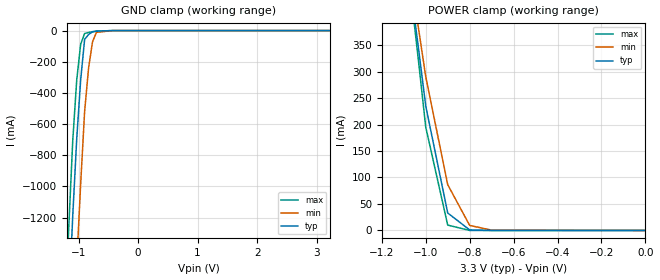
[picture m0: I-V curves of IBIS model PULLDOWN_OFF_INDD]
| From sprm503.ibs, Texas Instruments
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|   Model Cell PULLDOWN_OFF_INDD
[Model]   PULLDOWN_OFF_INDD
Model_type   Input
Polarity   Non-Inverting
Vinl =  0.8
Vinh =  2
C_comp   0.8695239p   0.8584917p   0.8767336p
[Model Spec]
Vinl   0.8   0.8   0.8
Vinh   2   2   2
[Temperature Range]   25   125   -40
[Voltage Range]   3.3   3.14   3.47
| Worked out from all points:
|   GND clamp passes 1 mA (typ) near -0.58 V on its own axis
|   POWER clamp passes 1 mA (typ) near -0.80 V on its own axis
[POWER_clamp]
|   voltage   I(typ)   I(min)   I(max)
-3.3V     9.572A     8.115A     10.87A
-1.067V   452.1mA    472.8mA    444.6mA
-1.033V   343.5mA    381.5mA    319.8mA
-1V       234.9mA    290.2mA    195mA
-900mV    33.01mA    86.46mA    10.14mA
-800mV    1.012mA    9.543mA    89.45uA
-700mV    23.28uA    605.6uA    712.3nA
-11.55fV  368.6pA    11.76nA    170.4pA
[GND_clamp]
|   voltage   I(typ)   I(min)   I(max)
-3.3V     -22.43A    -23.21A    -22A
-1.233V   -2.35A     -3.221A    -1.845A
-1.167V   -1.763A    -2.627A    -1.266A
-1.1V     -1.191A    -2.042A    -709.3mA
-1.033V   -696.7mA   -1.495A    -318mA
-966.7mV  -318.5mA   -986.5mA   -87.81mA
-900mV    -56.17mA   -518.4mA   -18.7mA
-833.3mV  -25.14mA   -240.3mA   -12.29mA
-766.7mV  -7.667mA   -71.25mA   -7.131mA
-700mV    -3.749mA   -11.22mA   -3.214mA
-433.3mV  -54.32uA   -212.5uA   -16.61uA
3.233V    348.5pA    12.42nA    146.2pA
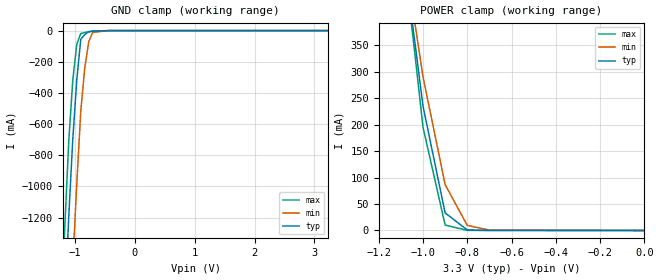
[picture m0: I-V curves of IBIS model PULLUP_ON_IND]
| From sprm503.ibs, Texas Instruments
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|   Model Cell PULLUP_ON_IND
[Model]   PULLUP_ON_IND
Model_type   Input
Polarity   Non-Inverting
Vinl =  0.8
Vinh =  2
C_comp   0.8695239p   0.8584917p   0.8767336p
[Model Spec]
Vinl   0.8   0.8   0.8
Vinh   2   2   2
[Temperature Range]   25   125   -40
[Voltage Range]   3.3   3.14   3.47
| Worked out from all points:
|   GND clamp passes 1 mA (typ) near -0.58 V on its own axis
|   POWER clamp passes 1 mA (typ) near -0.79 V on its own axis
[POWER_clamp]
|   voltage   I(typ)   I(min)   I(max)
-3.3V     9.572A     8.116A     10.87A
-1.067V   452.2mA    472.9mA    444.7mA
-1.033V   343.6mA    381.6mA    319.9mA
-1V       234.9mA    290.3mA    195.1mA
-900mV    33.09mA    86.55mA    10.25mA
-800mV    1.079mA    9.609mA    183.8uA
-700mV    81.06uA    649.2uA    81.95uA
-11.55fV  364pA      11.75nA    165.7pA
[GND_clamp]
|   voltage   I(typ)   I(min)   I(max)
-3.3V     -22.43A    -23.21A    -22A
-1.233V   -2.35A     -3.221A    -1.845A
-1.167V   -1.763A    -2.627A    -1.266A
-1.1V     -1.191A    -2.042A    -709.3mA
-1.033V   -696.7mA   -1.495A    -318mA
-966.7mV  -318.5mA   -986.5mA   -87.89mA
-900mV    -56.21mA   -518.4mA   -18.84mA
-833.3mV  -25.22mA   -240.3mA   -12.44mA
-766.7mV  -7.763mA   -71.27mA   -7.278mA
-700mV    -3.851mA   -11.26mA   -3.361mA
-433.3mV  -158uA     -278.1uA   -165.3uA
3.233V    -4.892uA   4.762uA    -23.3uA
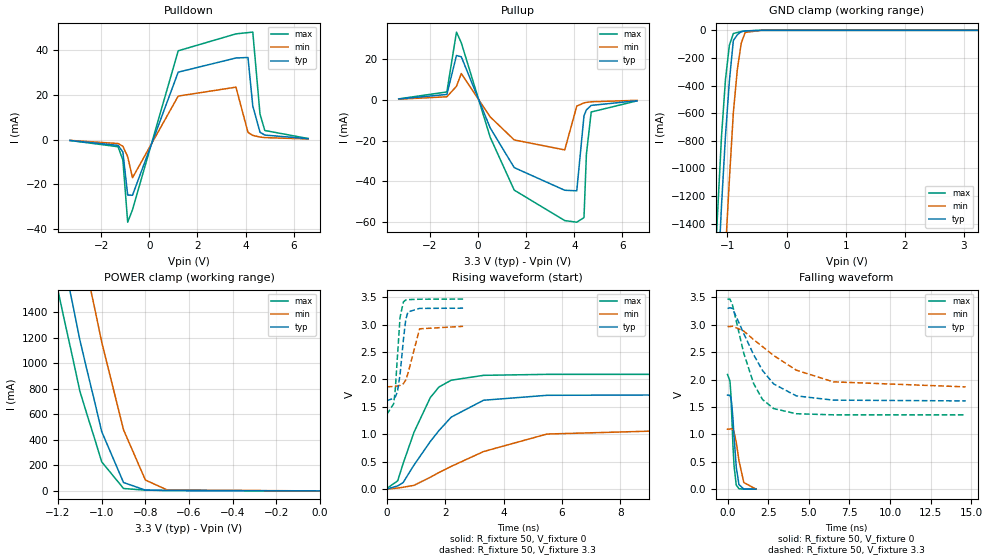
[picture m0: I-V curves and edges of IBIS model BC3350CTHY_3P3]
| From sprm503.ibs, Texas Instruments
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|   Model Cell BC3350CTHY_3P3
|BC3350CTHY_3P3
[Model]   BC3350CTHY_3P3
Model_type   I/O
Polarity   Non-Inverting
Enable   Active-Low
Vinl =  0.8V
Vinh =  2V
Cref =  15.0000pF
Rref =  100.0000M
Vref =  0V
Vmeas =  1.65
C_comp   0.8695239p   0.8584917p   0.8767304p
[Model Spec]
Vinl   0.8V   0.8V   0.8V
Vinh   2V   2V   2V
[Temperature Range]   25   125   -40
[Voltage Range]   3.3   2.97   3.465
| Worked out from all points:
|   slope of the pulldown table from 0 to 0.495 V, typ, clamps not added: 30.2 ohm
|   slope of the pullup table from 0 to 0.495 V, typ, clamps not added: 36.2 ohm
|   GND clamp passes 1 mA (typ) near -0.57 V on its own axis
|   POWER clamp passes 1 mA (typ) near -0.52 V on its own axis
|   rising waveform, R_fixture 50, V_fixture 0: 20-80 % time 1.52ns typ, 2.8ns min, 964ps max; typ from 0.001 V to 1.72 V
|   rising waveform, R_fixture 50, V_fixture 3.3: 20-80 % time 193ps typ, 277ps min, 154ps max; typ from 1.61 V to 3.3 V
|   falling waveform, R_fixture 50, V_fixture 0: 20-80 % time 242ps typ, 371ps min, 190ps max; typ from 1.72 V to 0.002 V
|   falling waveform, R_fixture 50, V_fixture 3.3: 20-80 % time 1.92ns typ, 3.36ns min, 1.32ns max; typ from 3.3 V to 1.61 V
[POWER_clamp]
|   voltage   I(typ)   I(min)   I(max)
-3.3V     22.37A     23.12A     21.96A
-1.2V     2.026A     2.853A     1.569A
-1.167V   1.745A     2.562A     1.307A
-1.133V   1.464A     2.272A     1.044A
-1.1V     1.183A     1.981A     781.8mA
-1.067V   943.8mA    1.709A     597.2mA
-1.033V   704.5mA    1.438A     412.6mA
-1V       465.3mA    1.167A     227.9mA
-900mV    65.74mA    478.8mA    18.97mA
-800mV    6.466mA    85.39mA    6.091mA
-700mV    3.149mA    7.546mA    3.832mA
0V        276.4pA    13.39nA    14.63pA
[Pulldown]
|   voltage   I(typ)   I(min)   I(max)
-3.3V     -379.4uA   -330.9uA   -386.9uA
-1.3V     -2.568mA   -1.749mA   -3.18mA
-1.1V     -5.533mA   -2.961mA   -9.161mA
-900mV    -24.8mA    -7.62mA    -36.98mA
-700mV    -24.92mA   -17.08mA   -31.4mA
1.2V      30.22mA    19.51mA    39.79mA
3.6V      36.57mA    23.5mA     47.37mA
4.1V      36.79mA    3.23mA     47.94mA
4.3V      15.06mA    1.903mA    48.17mA
4.6V      3.307mA    1.155mA    11.41mA
4.8V      2.043mA    911.3uA    4.087mA
6.6V      436uA      308.8uA    502.3uA
[Pullup]
|   voltage   I(typ)   I(min)   I(max)
-3.3V     352.6uA    257.6uA    391.7uA
-1.3V     2.559mA    1.411mA    3.79mA
-900mV    21.62mA    6.557mA    33.08mA
-700mV    21.01mA    12.8mA     27.85mA
500mV     -13.79mA   -8.403mA   -18.35mA
1.5V      -33.25mA   -19.7mA    -44.26mA
3.6V      -44.33mA   -24.58mA   -59.17mA
4.1V      -44.61mA   -3.141mA   -59.96mA
4.4V      -7.896mA   -1.57mA    -57.69mA
4.5V      -4.997mA   -1.34mA    -26.74mA
4.7V      -2.803mA   -1.033mA   -6.023mA
6.6V      -515.4uA   -319.6uA   -597.7uA
[GND_clamp]
|   voltage   I(typ)   I(min)   I(max)
-3.3V     -22.52A    -23.33A    -22.07A
-1.233V   -2.436A    -3.336A    -1.911A
-1.167V   -1.845A    -2.739A    -1.328A
-1.1V     -1.269A    -2.151A    -766.5mA
-1.033V   -763.8mA   -1.597A    -354.9mA
-966.7mV  -365.3mA   -1.079A    -107.1mA
-900mV    -73.52mA   -596.8mA   -23.28mA
-833.3mV  -32.6mA    -287.4mA   -15.31mA
-766.7mV  -9.652mA   -93.47mA   -8.887mA
-700mV    -4.682mA   -15.11mA   -4.019mA
-433.3mV  -68.38uA   -267.7uA   -20.98uA
3.233V    -607.5pA   11.45uA    -20pA
[Ramp]
| variable   typ   min   max
dV/dt_f   1.022976/1.927517n   0.6709498/3.398073n   1.276353/1.319437n
dV/dt_r   1.031671/1.520254n   0.6578422/2.813193n   1.25571/0.9666258n
R_load = 50
[Rising Waveform]
R_fixture = 50
V_fixture = 0
V_fixture_min = 0
V_fixture_max = 0
|   time   V(typ)   V(min)   V(max)
0s        1.187mV    -365.6uV   12.72mV
372ps     59.43mV    20.3mV     151.3mV
558ps     119.7mV    34.65mV    465.9mV
933ps     440.9mV    69.38mV    1.039V
1.491ns   869.1mV    217.2mV    1.67V
1.785ns   1.067V     302.6mV    1.861V
2.205ns   1.312V     414.5mV    1.985V
3.312ns   1.62V      684.7mV    2.074V
5.484ns   1.71V      1.004V     2.092V
11.43ns   1.719V     1.093V     2.092V
[Rising Waveform]
R_fixture = 50
V_fixture = 3.3
V_fixture_min = 2.97
V_fixture_max = 3.465
|   time   V(typ)   V(min)   V(max)
0s        1.612V     1.865V     1.362V
237ps     1.657V     1.87V      1.558V
291ps     1.681V     1.875V     1.821V
363ps     1.772V     1.882V     2.412V
453ps     2.084V     1.891V     3.13V
567ps     2.717V     1.922V     3.412V
648ps     3.088V     1.99V      3.446V
723ps     3.229V     2.105V     3.454V
1.122ns   3.294V     2.922V     3.461V
2.613ns   3.298V     2.967V     3.464V
[Falling Waveform]
R_fixture = 50
V_fixture = 0
V_fixture_min = 0
V_fixture_max = 0
|   time   V(typ)   V(min)   V(max)
0s        1.719V     1.096V     2.094V
150ps     1.713V     1.097V     1.975V
201ps     1.672V     1.101V     1.758V
252ps     1.584V     1.104V     1.406V
336ps     1.281V     1.086V     788.4mV
402ps     958.1mV    1.044V     428.2mV
537ps     402.8mV    856.9mV    77.62mV
705ps     83.71mV    520.9mV    7.935mV
1.002ns   4.674mV    122.6mV    2.2mV
1.749ns   1.531mV    2.984mV    1.095mV
[Falling Waveform]
R_fixture = 50
V_fixture = 3.3
V_fixture_min = 2.97
V_fixture_max = 3.465
|   time   V(typ)   V(min)   V(max)
0s        3.299V     2.97V      3.471V
153ps     3.313V     2.969V     3.469V
306ps     3.299V     2.976V     3.363V
996ps     2.844V     2.888V     2.487V
1.608ns   2.455V     2.73V      1.928V
2.151ns   2.169V     2.604V     1.639V
2.838ns   1.922V     2.441V     1.472V
4.233ns   1.704V     2.173V     1.378V
6.51ns    1.626V     1.96V      1.358V
14.66ns   1.612V     1.868V     1.357V
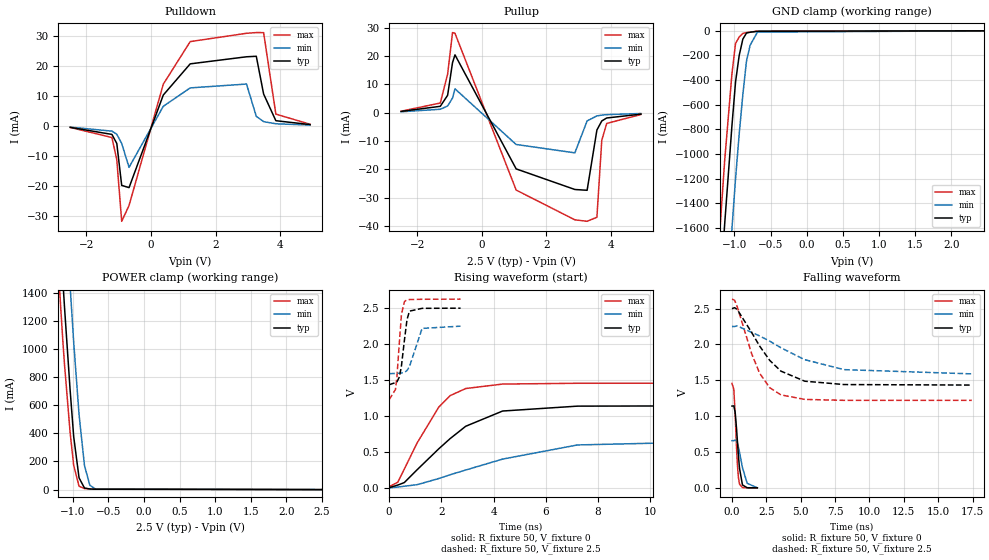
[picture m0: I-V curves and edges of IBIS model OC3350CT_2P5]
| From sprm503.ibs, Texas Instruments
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|   Model Cell OC3350CT_2P5
|OC3350CT_2P5
[Model]   OC3350CT_2P5
Model_type   3-state
Polarity   Non-Inverting
Enable   Active-Low
Cref =  15.0000pF
Rref =  100.0000M
Vref =  0V
Vmeas =  1.25
C_comp   1.347692p   1.333424p   1.364961p
[Temperature Range]   25   125   -40
[Voltage Range]   2.5   2.25   2.625
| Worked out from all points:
|   slope of the pulldown table from 0 to 0.375 V, typ, clamps not added: 36.8 ohm
|   slope of the pullup table from 0 to 0.375 V, typ, clamps not added: 43.3 ohm
|   GND clamp passes 1 mA (typ) near -0.58 V on its own axis
|   POWER clamp passes 1 mA (typ) near -0.52 V on its own axis
|   rising waveform, R_fixture 50, V_fixture 0: 20-80 % time 2.17ns typ, 3.87ns min, 1.36ns max; typ from 0.002 V to 1.14 V
|   rising waveform, R_fixture 50, V_fixture 2.5: 20-80 % time 211ps typ, 315ps min, 166ps max; typ from 1.43 V to 2.5 V
|   falling waveform, R_fixture 50, V_fixture 0: 20-80 % time 274ps typ, 441ps min, 205ps max; typ from 1.14 V to 0.001 V
|   falling waveform, R_fixture 50, V_fixture 2.5: 20-80 % time 2.38ns typ, 4.28ns min, 1.65ns max; typ from 2.5 V to 1.43 V
[POWER_clamp]
|   voltage   I(typ)   I(min)   I(max)
-2.5V     14.49A     15.27A     14.05A
-1.187V   1.915A     2.738A     1.465A
-1.162V   1.698A     2.516A     1.258A
-1.136V   1.481A     2.293A     1.051A
-1.111V   1.28A      2.079A     875.8mA
-1.035V   711.3mA    1.451A     408.3mA
-984.8mV  377.8mA    1.051A     173mA
-909.1mV  83.47mA    532.5mA    24.21mA
-833.3mV  11.42mA    171.8mA    7.264mA
-757.6mV  4.351mA    30.7mA     5.044mA
-681.8mV  2.867mA    5.071mA    3.48mA
2.5V      125.4pA    8.964nA    3.721pA
[Pulldown]
|   voltage   I(typ)   I(min)   I(max)
-2.5V     -481.1uA   -397.2uA   -508.7uA
-1.212V   -2.822mA   -1.735mA   -3.851mA
-1.061V   -5.825mA   -2.764mA   -11.26mA
-909.1mV  -19.76mA   -5.836mA   -31.7mA
-681.8mV  -20.51mA   -13.77mA   -26.47mA
378.8mV   10.27mA    6.528mA    13.88mA
1.212V    20.63mA    12.64mA    28.03mA
2.955V    22.98mA    13.92mA    30.79mA
3.258V    23.15mA    3.189mA    31.03mA
3.485V    10.6mA     1.427mA    31.01mA
3.864V    1.733mA    710uA      3.927mA
4.924V    445.6uA    287.2uA    553.5uA
[Pullup]
|   voltage   I(typ)   I(min)   I(max)
-2.5V     459.9uA    322.6uA    529.4uA
-1.288V   2.256mA    1.218mA    3.421mA
-1.061V   6.151mA    2.378mA    13.64mA
-909.1mV  17.71mA    5.194mA    28.32mA
-833.3mV  20.44mA    8.44mA     28.06mA
1.061V    -19.86mA   -11.24mA   -27.34mA
2.879V    -27.14mA   -14.19mA   -37.86mA
3.258V    -27.42mA   -2.905mA   -38.38mA
3.561V    -6.115mA   -1.137mA   -36.94mA
3.712V    -2.921mA   -859.8uA   -9.771mA
3.864V    -1.868mA   -688.9uA   -3.791mA
4.924V    -509.6uA   -284.1uA   -641.8uA
[GND_clamp]
|   voltage   I(typ)   I(min)   I(max)
-2.5V     -14.63A    -15.47A    -14.16A
-1.237V   -2.471A    -3.372A    -1.946A
-1.187V   -2.02A     -2.917A    -1.498A
-1.136V   -1.576A    -2.468A    -1.06A
-1.035V   -772.6mA   -1.611A    -351.6mA
-984.8mV  -415.4mA   -1.201A    -101.8mA
-934.3mV  -199.7mA   -837.2mA   -50.59mA
-883.8mV  -67.23mA   -518.2mA   -21.44mA
-833.3mV  -18.12mA   -244.5mA   -14.33mA
-782.8mV  -11.39mA   -116.8mA   -9.9mA
-681.8mV  -3.783mA   -10.47mA   -3.061mA
2.449V    -731.5pA   2.278uA    -25.67pA
[Ramp]
| variable   typ   min   max
dV/dt_f  0.6473712/2.404478n   0.4030882/4.355322n   0.8515609/1.650441n
dV/dt_r  0.6849599/2.170112n   0.3951728/3.894028n   0.8729831/1.370713n
R_load = 50
[Rising Waveform]
R_fixture = 50
V_fixture = 0
V_fixture_min = 0
V_fixture_max = 0
|   time   V(typ)   V(min)   V(max)
0s        2.227mV    -460.6uV   16.44mV
330ps     38.21mV    10.47mV    77.08mV
579ps     73.02mV    22.38mV    260.1mV
1.074ns   252.4mV    43.88mV    625.9mV
1.902ns   543.2mV    129.6mV    1.123V
2.34ns    685.6mV    182.3mV    1.283V
2.934ns   856.3mV    247.6mV    1.381V
4.347ns   1.068V     399.7mV    1.443V
7.212ns   1.136V     596.2mV    1.454V
14.33ns   1.141V     655.9mV    1.455V
[Rising Waveform]
R_fixture = 50
V_fixture = 2.5
V_fixture_min = 2.25
V_fixture_max = 2.625
|   time   V(typ)   V(min)   V(max)
0s        1.434V     1.588V     1.225V
243ps     1.463V     1.59V      1.368V
300ps     1.474V     1.593V     1.551V
393ps     1.543V     1.596V     2.035V
471ps     1.696V     1.598V     2.411V
585ps     2.054V     1.605V     2.59V
684ps     2.339V     1.631V     2.614V
777ps     2.457V     1.685V     2.618V
1.263ns   2.496V     2.217V     2.622V
2.736ns   2.498V     2.248V     2.624V
[Falling Waveform]
R_fixture = 50
V_fixture = 0
V_fixture_min = 0
V_fixture_max = 0
|   time   V(typ)   V(min)   V(max)
0s        1.141V     658.3mV    1.457V
132ps     1.144V     658.7mV    1.378V
234ps     1.051V     666.9mV    1.02V
336ps     816mV      653.8mV    542.2mV
402ps     628.4mV    621.8mV    304.1mV
468ps     449.3mV    572.4mV    148.8mV
546ps     276.5mV    499.7mV    52.58mV
762ps     41.17mV    283mV      4.68mV
1.104ns   2.902mV    64.62mV    1.623mV
1.842ns   1.18mV     2.257mV    892.1uV
[Falling Waveform]
R_fixture = 50
V_fixture = 2.5
V_fixture_min = 2.25
V_fixture_max = 2.625
|   time   V(typ)   V(min)   V(max)
0s        2.499V     2.25V      2.632V
192ps     2.513V     2.251V     2.616V
381ps     2.488V     2.258V     2.526V
1.434ns   2.166V     2.169V     1.869V
2.007ns   1.979V     2.119V     1.6V
2.745ns   1.778V     2.046V     1.397V
3.561ns   1.628V     1.954V     1.297V
5.292ns   1.488V     1.788V     1.234V
8.157ns   1.441V     1.649V     1.221V
17.44ns   1.434V     1.59V      1.221V
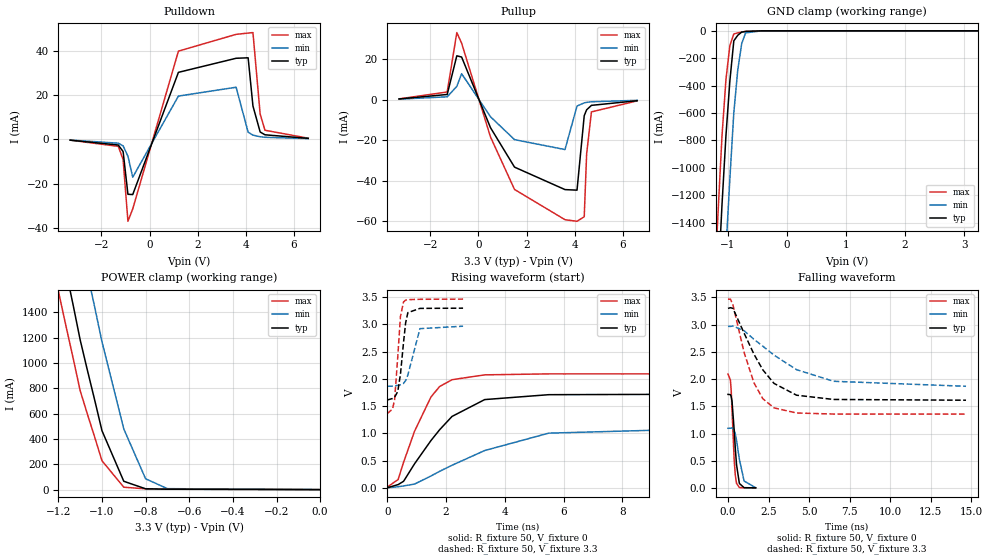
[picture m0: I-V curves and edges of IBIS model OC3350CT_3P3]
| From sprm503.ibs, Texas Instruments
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|   Model Cell OC3350CT_3P3
|OC3350CT_3P3
[Model]   OC3350CT_3P3
Model_type   3-state
Polarity   Non-Inverting
Enable   Active-Low
Cref =  15.0000pF
Rref =  100.0000M
Vref =  0V
Vmeas =  1.65
C_comp   1.313883p   1.304852p   1.321238p
[Temperature Range]   25   125   -40
[Voltage Range]   3.3   2.97   3.465
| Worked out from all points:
|   slope of the pulldown table from 0 to 0.495 V, typ, clamps not added: 30.2 ohm
|   slope of the pullup table from 0 to 0.495 V, typ, clamps not added: 36.2 ohm
|   GND clamp passes 1 mA (typ) near -0.57 V on its own axis
|   POWER clamp passes 1 mA (typ) near -0.52 V on its own axis
|   rising waveform, R_fixture 50, V_fixture 0: 20-80 % time 1.53ns typ, 2.81ns min, 967ps max; typ from 0.001 V to 1.72 V
|   rising waveform, R_fixture 50, V_fixture 3.3: 20-80 % time 191ps typ, 276ps min, 151ps max; typ from 1.61 V to 3.3 V
|   falling waveform, R_fixture 50, V_fixture 0: 20-80 % time 237ps typ, 369ps min, 185ps max; typ from 1.72 V to 0.002 V
|   falling waveform, R_fixture 50, V_fixture 3.3: 20-80 % time 1.92ns typ, 3.36ns min, 1.31ns max; typ from 3.3 V to 1.61 V
[POWER_clamp]
|   voltage   I(typ)   I(min)   I(max)
-3.3V     22.37A     23.12A     21.96A
-1.2V     2.026A     2.853A     1.569A
-1.167V   1.745A     2.562A     1.307A
-1.133V   1.464A     2.272A     1.044A
-1.1V     1.183A     1.981A     781.8mA
-1.067V   943.8mA    1.709A     597.2mA
-1.033V   704.5mA    1.438A     412.6mA
-1V       465.3mA    1.167A     227.9mA
-900mV    65.74mA    478.8mA    18.97mA
-800mV    6.466mA    85.39mA    6.091mA
-700mV    3.149mA    7.546mA    3.832mA
0V        271.8pA    13.17nA    14.38pA
[Pulldown]
|   voltage   I(typ)   I(min)   I(max)
-3.3V     -379.4uA   -330.9uA   -386.8uA
-1.3V     -2.567mA   -1.749mA   -3.179mA
-1.1V     -5.531mA   -2.961mA   -9.157mA
-900mV    -24.8mA    -7.618mA   -36.99mA
-700mV    -24.92mA   -17.09mA   -31.4mA
1.2V      30.22mA    19.51mA    39.79mA
3.6V      36.57mA    23.5mA     47.37mA
4.1V      36.79mA    3.23mA     47.94mA
4.3V      15.06mA    1.903mA    48.17mA
4.6V      3.307mA    1.155mA    11.41mA
4.8V      2.043mA    911.3uA    4.087mA
6.6V      436uA      308.8uA    502.3uA
[Pullup]
|   voltage   I(typ)   I(min)   I(max)
-3.3V     352.6uA    257.6uA    391.7uA
-1.3V     2.559mA    1.411mA    3.79mA
-900mV    21.62mA    6.557mA    33.08mA
-700mV    21.01mA    12.8mA     27.85mA
500mV     -13.79mA   -8.403mA   -18.35mA
1.5V      -33.25mA   -19.7mA    -44.26mA
3.6V      -44.33mA   -24.59mA   -59.17mA
4.1V      -44.61mA   -3.14mA    -59.96mA
4.4V      -7.894mA   -1.57mA    -57.7mA
4.5V      -4.996mA   -1.339mA   -26.73mA
4.7V      -2.802mA   -1.033mA   -6.021mA
6.6V      -515.3uA   -319.6uA   -597.7uA
[GND_clamp]
|   voltage   I(typ)   I(min)   I(max)
-3.3V     -22.52A    -23.33A    -22.07A
-1.233V   -2.436A    -3.336A    -1.911A
-1.167V   -1.845A    -2.739A    -1.328A
-1.1V     -1.269A    -2.151A    -766.4mA
-1.033V   -763.7mA   -1.597A    -354.6mA
-966.7mV  -365mA     -1.079A    -106.8mA
-900mV    -73.25mA   -596.7mA   -23.01mA
-833.3mV  -32.41mA   -287.2mA   -15.12mA
-766.7mV  -9.532mA   -93.27mA   -8.77mA
-700mV    -4.617mA   -14.97mA   -3.962mA
-433.3mV  -67.28uA   -263.4uA   -20.63uA
3.233V    -611.8pA   11.45uA    -20.17pA
[Ramp]
| variable   typ   min   max
dV/dt_f   1.023028/1.927535n   0.6709752/3.396968n   1.27642/1.318548n
dV/dt_r   1.031675/1.525599n   0.6578465/2.823834n   1.255713/0.9699551n
R_load = 50
[Rising Waveform]
R_fixture = 50
V_fixture = 0
V_fixture_min = 0
V_fixture_max = 0
|   time   V(typ)   V(min)   V(max)
0s        1.229mV    -372.9uV   12.96mV
372ps     59.76mV    20.56mV    153.2mV
558ps     120.9mV    34.88mV    472.2mV
930ps     441.7mV    69.31mV    1.039V
1.488ns   868.2mV    217.5mV    1.668V
1.782ns   1.066V     302.8mV    1.86V
2.205ns   1.311V     414.8mV    1.985V
3.315ns   1.62V      684.7mV    2.074V
5.493ns   1.71V      1.004V     2.092V
11.44ns   1.719V     1.093V     2.092V
[Rising Waveform]
R_fixture = 50
V_fixture = 3.3
V_fixture_min = 2.97
V_fixture_max = 3.465
|   time   V(typ)   V(min)   V(max)
0s        1.612V     1.865V     1.362V
180ps     1.64V      1.866V     1.446V
252ps     1.663V     1.871V     1.619V
360ps     1.77V      1.882V     2.413V
450ps     2.082V     1.891V     3.145V
555ps     2.669V     1.917V     3.413V
627ps     3.03V      1.97V      3.446V
702ps     3.216V     2.072V     3.454V
1.113ns   3.294V     2.922V     3.461V
2.58ns    3.298V     2.967V     3.464V
[Falling Waveform]
R_fixture = 50
V_fixture = 0
V_fixture_min = 0
V_fixture_max = 0
|   time   V(typ)   V(min)   V(max)
0s        1.719V     1.096V     2.093V
150ps     1.714V     1.097V     1.981V
198ps     1.678V     1.101V     1.783V
249ps     1.594V     1.104V     1.435V
381ps     1.062V     1.061V     513.2mV
450ps     724.5mV    993.9mV    238.1mV
525ps     429.7mV    878.9mV    85.28mV
702ps     81.83mV    524.3mV    6.868mV
993ps     4.301mV    127.4mV    2.09mV
1.707ns   1.501mV    2.994mV    1.101mV
[Falling Waveform]
R_fixture = 50
V_fixture = 3.3
V_fixture_min = 2.97
V_fixture_max = 3.465
|   time   V(typ)   V(min)   V(max)
0s        3.299V     2.97V      3.47V
153ps     3.313V     2.969V     3.469V
306ps     3.299V     2.976V     3.364V
996ps     2.843V     2.888V     2.486V
1.608ns   2.454V     2.73V      1.927V
2.148ns   2.17V      2.605V     1.639V
2.838ns   1.921V     2.441V     1.471V
4.23ns    1.704V     2.173V     1.377V
6.51ns    1.626V     1.96V      1.358V
14.68ns   1.612V     1.868V     1.357V
